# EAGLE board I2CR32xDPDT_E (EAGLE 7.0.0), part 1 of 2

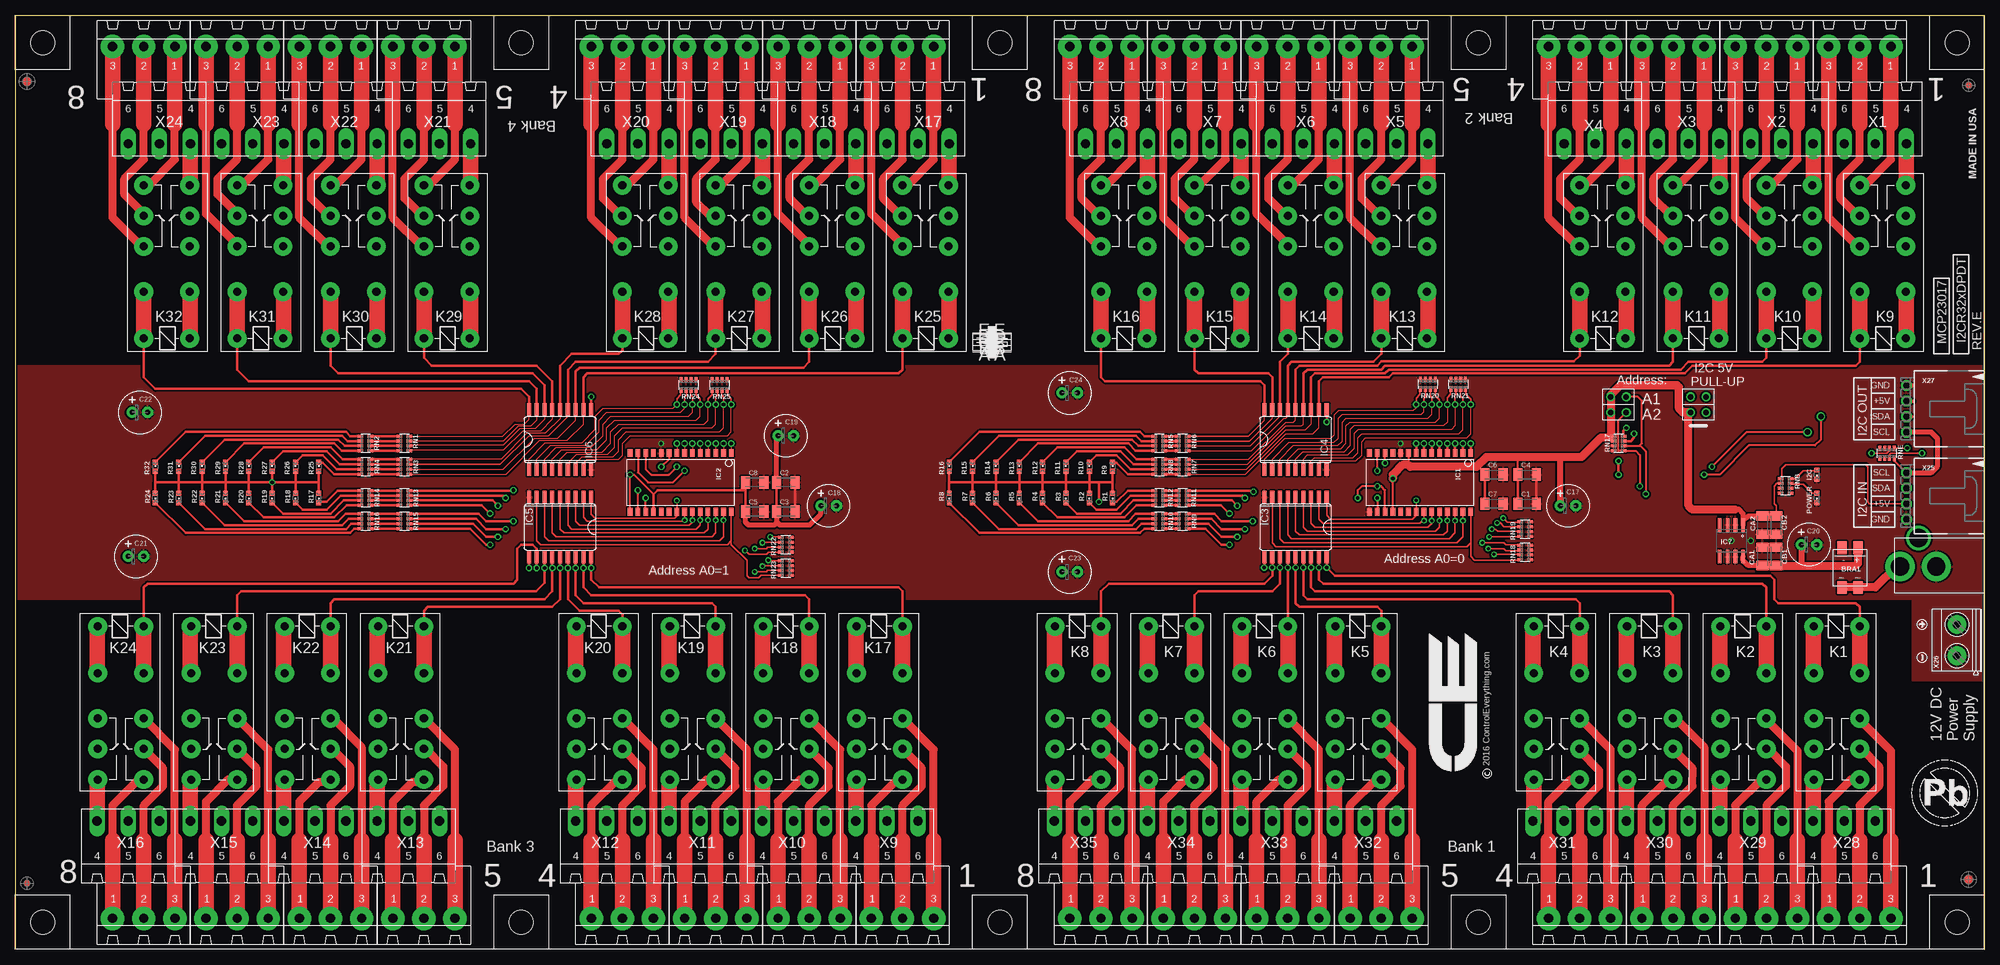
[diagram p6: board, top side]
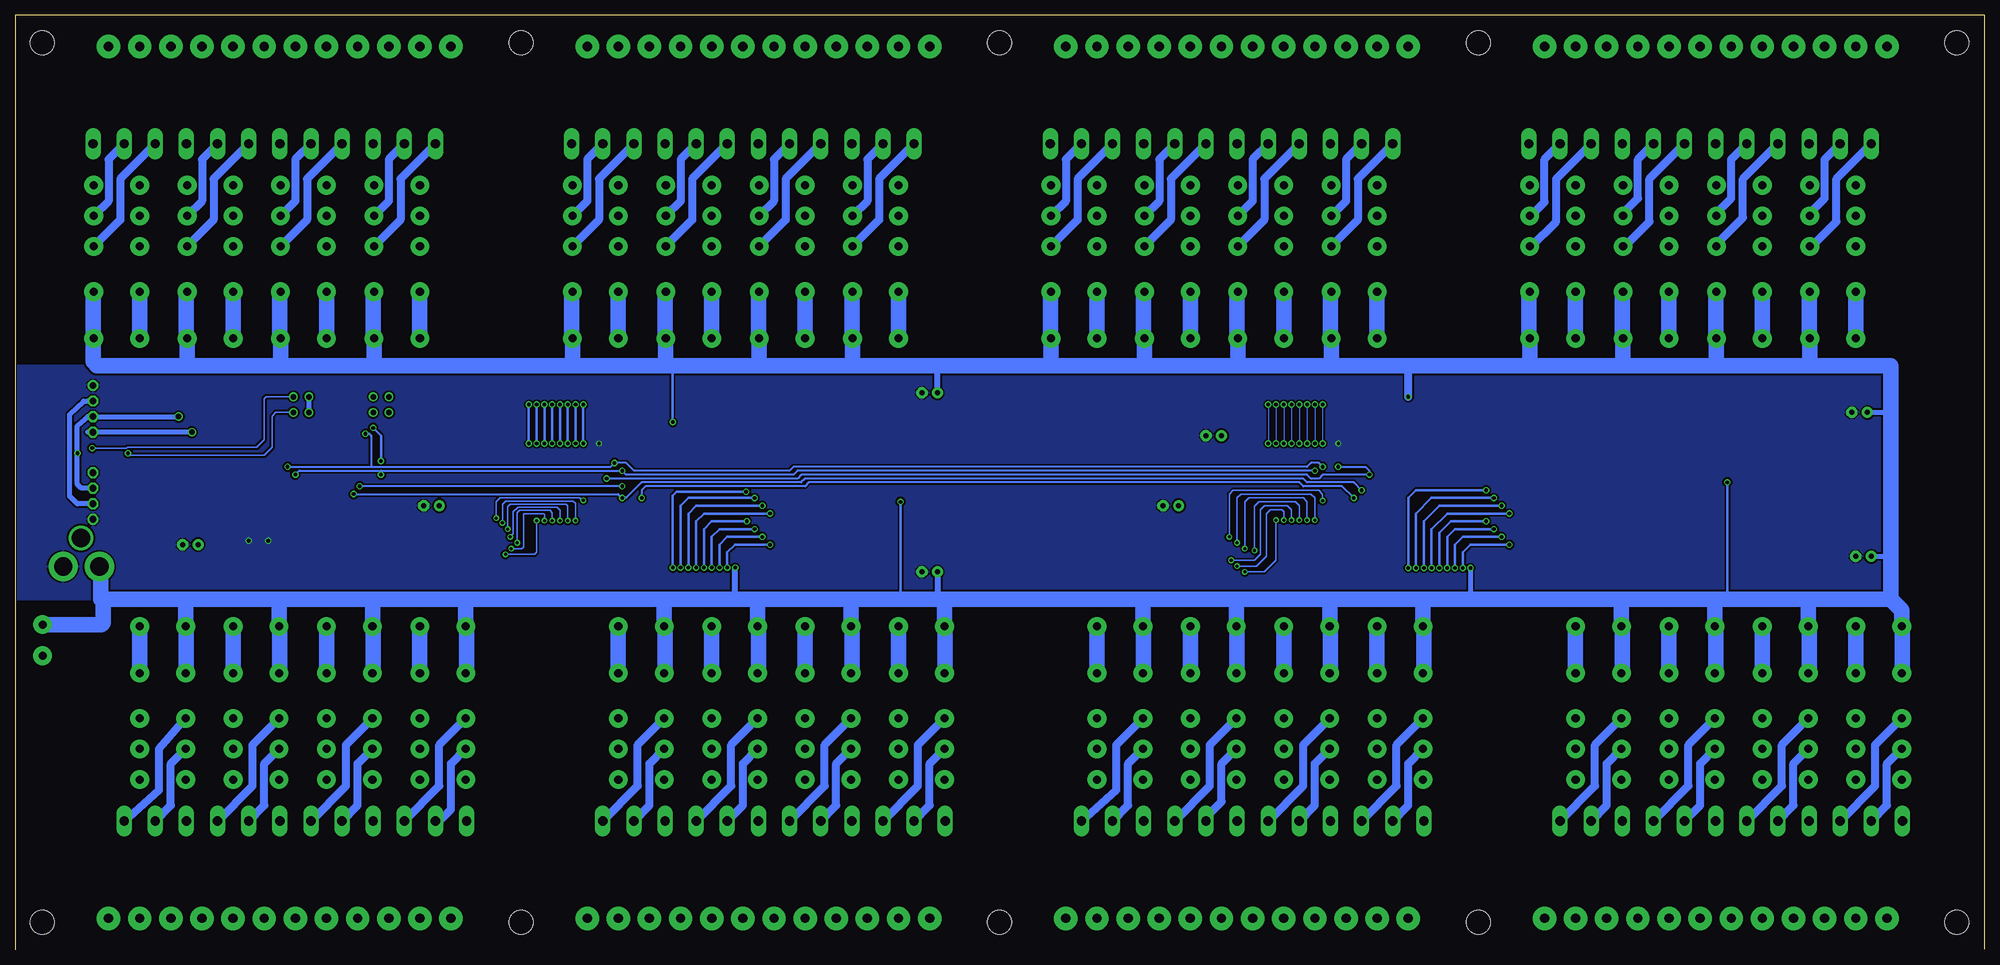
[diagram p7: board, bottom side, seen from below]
Size 321.29 x 152.41 mm. Coordinates in mm from the lower left corner, seen from the top.
Outline: 321.29,0 321.29,152.41 0,152.41 0,0.01
Copper layers (1*16): Top 0.035mm / dielectric 1.5mm / Bottom 0.035mm
Design rules "default": minimum track width 5mil, minimum drill 24mil, track to track 5mil, track to pad 5mil, pad to pad 5mil, via to via 5mil, smd to smd 5mil, copper to edge 10mil, drill to drill 8mil, minimum pad ring 10mil, minimum via ring 8mil, stop-mask expansion 2mil, vias tented up to drill 0mil, thermal gap 10mil

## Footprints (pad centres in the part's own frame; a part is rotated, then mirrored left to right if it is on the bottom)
MB2S = smd 1.55 x 2.1: + 0,-6.5; - 2.54,-6.5; ~@1 0,0; ~@2 2.54,0
_CA_.1UF_50V = smd 1.5 x 2: 1 -1.5,0; 2 1.5,0
_CB_10UF_25V = smd 1.5 x 2: 1 -1.5,0; 2 1.5,0
E-025X060 = drill 0.813 pad 1.778: + -1.27,0 | drill 0.813 pad 1.778 octagon: - 1.27,0
CC1206KRX7R9BB104 = smd 1.5 x 2: 1 -1.5,0; 2 1.5,0
TMK316F106ZL-T = smd 1.5 x 2: 1 -1.5,0; 2 1.5,0
CHIPLED_0603 = smd 0.8 x 0.8: A 0,-0.75; C 0,0.75
SO28W = smd 0.762 x 1.27: 1 -7.62,-4.78; 2 -6.35,-4.78; 3 -5.08,-4.78; 4 -3.81,-4.78; 5 -2.54,-4.78; 6 -1.27,-4.78; 7 0,-4.78; 8 1.27,-4.78; 9 2.54,-4.78; 10 3.81,-4.78; 11 5.08,-4.78; 12 6.35,-4.78; 13 7.62,-4.78; 14 8.89,-4.78; 15 8.89,4.78; 16 7.62,4.78; 17 6.35,4.78; 18 5.08,4.78; 19 3.81,4.78; 20 2.54,4.78; 21 1.27,4.78; 22 0,4.78; 23 -1.27,4.78; 24 -2.54,4.78; 25 -3.81,4.78; 26 -5.08,4.78; 27 -6.35,4.78; 28 -7.62,4.78
SO18L = smd 0.66 x 2.032: 1 -5.08,-4.902; 2 -3.81,-4.902; 3 -2.54,-4.902; 4 -1.27,-4.902; 5 0,-4.902; 6 1.27,-4.902; 7 2.54,-4.902; 8 3.81,-4.902; 9 5.08,-4.902; 10 5.08,4.902; 11 3.81,4.902; 12 2.54,4.902; 13 1.27,4.902; 14 0,4.902; 15 -1.27,4.902; 16 -2.54,4.902; 17 -3.81,4.902; 18 -5.08,4.902
_RGC_5V_SOIC8 = smd 0.6 x 2.2: 1 -1.905,-2.6; 2 -0.635,-2.6; 3 0.635,-2.6; 4 1.905,-2.6; 5 1.905,2.6; 6 0.635,2.6; 7 -0.635,2.6; 8 -1.905,2.6
G2R2 = drill 1.321 pad 3.048: 1 -2.54,-3.683; 2 -2.54,3.81; 3 5.08,-3.683; 4 5.08,3.81; O1 12.471,3.81; O2 12.471,-3.683; P1 17.45,3.81; P2 17.45,-3.683; S1 22.454,3.81; S2 22.454,-3.683
RNB = smd 0.5 x 0.9: 1 -1.2,-0.8; 2 -0.4,-0.8; 3 0.4,-0.8; 4 1.2,-0.8; 5 1.2,0.8; 6 0.4,0.8; 7 -0.4,0.8; 8 -1.2,0.8
RNE = smd 0.5 x 0.9: 1 -1.2,-0.8; 2 -0.4,-0.8; 3 0.4,-0.8; 4 1.2,-0.8; 5 1.2,0.8; 6 0.4,0.8; 7 -0.4,0.8; 8 -1.2,0.8
RND = smd 0.5 x 0.9: 1 -1.2,-0.8; 2 -0.4,-0.8; 3 0.4,-0.8; 4 1.2,-0.8; 5 1.2,0.8; 6 0.4,0.8; 7 -0.4,0.8; 8 -1.2,0.8
PCB_MOUNTING_HOLE = hole 3.962: 4.445,4.445
JUMPER_2X2 = drill 0.9: A1 0,2.54; A2 0,0; B1 2.54,2.54; B2 2.54,0
PJ-102A = drill 3 pad 4.8: RING 0.1,-3.39; TIP 0.1,-9.29 | drill 3 pad 3.251: RING_SW -4.6,-6.29
MDSTB3 = drill 1.524 pad 3.81: 1 -3.81,-10.795; 2 1.27,-10.795; 3 6.35,-10.795 | drill 1.524 pad 2.54 long: 4 -6.35,5.08; 5 -1.27,5.08; 6 3.81,5.08
15-91-04 = drill 1.1 pad 1.778 octagon: 1 -3.81,-7.62; 2 -1.27,-7.62; 3 1.27,-7.62; 4 3.81,-7.62
MKDSN1,5/2-5,08 = drill 1.3 pad 3.048: 1 -2.561,0.025; 2 2.519,0.025

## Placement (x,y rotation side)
BRA1  MB2S_  [MB2S]  300.67,59.07 180 top
C1  [_CA_.1UF_50V]  246.7,72.72 0 top
C2  _CB_10UF_25VC1206K  [_CB_10UF_25V]  125.73,76.21 0 top
C3  [_CA_.1UF_50V]  125.73,71.45 0 top
C4  _CB_10UF_25VC1206K  [_CB_10UF_25V]  246.7,77.48 0 top
C5  [_CA_.1UF_50V]  120.65,71.45 0 top
C6  _CB_10UF_25VC1206K  [_CB_10UF_25V]  241.3,77.48 0 top
C7  [_CA_.1UF_50V]  241.3,72.72 0 top
C8  _CB_10UF_25VC1206K  [_CB_10UF_25V]  120.65,76.21 0 top
C17  100uF  [E-025X060]  253.37,72.4 0 top
C18  100uF  [E-025X060]  132.72,72.4 0 top
C19  100uF  [E-025X060]  125.73,83.83 0 top
C20  100uF  [E-025X060]  292.74,66.05 0 top
C21  100uF  [E-025X060]  19.68,64.15 0 top
C22  100uF  [E-025X060]  20.32,87.64 0 top
C23  100uF  [E-025X060]  172.09,61.61 0 top
C24  100uF  [E-025X060]  172.09,90.82 0 top
CA1  [CC1206KRX7R9BB104]  285.12,64.15 270 top
CA2  [CC1206KRX7R9BB104]  285.12,69.23 90 top
CB1  [TMK316F106ZL-T]  287.34,64.15 270 top
CB2  [TMK316F106ZL-T]  287.34,69.23 90 top
I2C  LED_NCD  [CHIPLED_0603]  294,77.48 180 top
IC1  MCP23017SO  [SO28W]  229.87,76.21 180 top
IC2  MCP23017SO  [SO28W]  109.22,76.21 180 top
IC3  ULN2803  [SO18L]  208.91,68.91 180 top
IC4  ULN2803  [SO18L]  208.91,83.2 0 top
IC5  ULN2803  [SO18L]  88.9,68.91 180 top
IC6  ULN2803  [SO18L]  88.9,83.2 0 top
IC7  _RGC_5V_SOIC805  [_RGC_5V_SOIC8]  280.04,66.69 180 top
K1  G2R2  [G2R2]  297.18,50.18 270 top
K2  G2R2  [G2R2]  281.94,50.18 270 top
K3  G2R2  [G2R2]  266.7,50.18 270 top
K4  G2R2  [G2R2]  251.46,50.18 270 top
K5  G2R2  [G2R2]  219.07,50.18 270 top
K6  G2R2  [G2R2]  203.84,50.18 270 top
K7  G2R2  [G2R2]  188.59,50.18 270 top
K8  G2R2  [G2R2]  173.35,50.18 270 top
K9  G2R2  [G2R2]  304.8,102.25 90 top
K10  G2R2  [G2R2]  289.56,102.25 90 top
K11  G2R2  [G2R2]  274.32,102.25 90 top
K12  G2R2  [G2R2]  259.08,102.25 90 top
K13  G2R2  [G2R2]  226.69,102.25 90 top
K14  G2R2  [G2R2]  211.46,102.25 90 top
K15  G2R2  [G2R2]  196.22,102.25 90 top
K16  G2R2  [G2R2]  180.97,102.25 90 top
K17  G2R2  [G2R2]  140.97,50.18 270 top
K18  G2R2  [G2R2]  125.73,50.18 270 top
K19  G2R2  [G2R2]  110.49,50.18 270 top
K20  G2R2  [G2R2]  95.25,50.18 270 top
K21  G2R2  [G2R2]  62.87,50.18 270 top
K22  G2R2  [G2R2]  47.62,50.18 270 top
K23  G2R2  [G2R2]  32.38,50.18 270 top
K24  G2R2  [G2R2]  17.14,50.18 270 top
K25  G2R2  [G2R2]  148.59,102.25 90 top
K26  G2R2  [G2R2]  133.35,102.25 90 top
K27  G2R2  [G2R2]  118.11,102.25 90 top
K28  G2R2  [G2R2]  102.87,102.25 90 top
K29  G2R2  [G2R2]  70.48,102.25 90 top
K30  G2R2  [G2R2]  55.24,102.25 90 top
K31  G2R2  [G2R2]  40.01,102.25 90 top
K32  G2R2  [G2R2]  24.77,102.25 90 top
POWER  LED_NCD  [CHIPLED_0603]  294,73.67 180 top
R1  LED_NCD  [CHIPLED_0603]  179.07,73.67 180 top
R2  LED_NCD  [CHIPLED_0603]  175.26,73.67 180 top
R3  LED_NCD  [CHIPLED_0603]  171.45,73.67 180 top
R4  LED_NCD  [CHIPLED_0603]  167.64,73.67 180 top
R5  LED_NCD  [CHIPLED_0603]  163.83,73.67 180 top
R6  LED_NCD  [CHIPLED_0603]  160.02,73.67 180 top
R7  LED_NCD  [CHIPLED_0603]  156.21,73.67 180 top
R8  LED_NCD  [CHIPLED_0603]  152.4,73.67 180 top
R9  LED_NCD  [CHIPLED_0603]  179.07,78.75 0 top
R10  LED_NCD  [CHIPLED_0603]  175.26,78.75 0 top
R11  LED_NCD  [CHIPLED_0603]  171.45,78.75 0 top
R12  LED_NCD  [CHIPLED_0603]  167.64,78.75 0 top
R13  LED_NCD  [CHIPLED_0603]  163.83,78.75 0 top
R14  LED_NCD  [CHIPLED_0603]  160.02,78.75 0 top
R15  LED_NCD  [CHIPLED_0603]  156.21,78.75 0 top
R16  LED_NCD  [CHIPLED_0603]  152.4,78.75 0 top
R17  LED_NCD  [CHIPLED_0603]  49.53,73.67 180 top
R18  LED_NCD  [CHIPLED_0603]  45.72,73.67 180 top
R19  LED_NCD  [CHIPLED_0603]  41.91,73.67 180 top
R20  LED_NCD  [CHIPLED_0603]  38.1,73.67 180 top
R21  LED_NCD  [CHIPLED_0603]  34.29,73.67 180 top
R22  LED_NCD  [CHIPLED_0603]  30.48,73.67 180 top
R23  LED_NCD  [CHIPLED_0603]  26.67,73.67 180 top
R24  LED_NCD  [CHIPLED_0603]  22.86,73.67 180 top
R25  LED_NCD  [CHIPLED_0603]  49.53,78.75 0 top
R26  LED_NCD  [CHIPLED_0603]  45.72,78.75 0 top
R27  LED_NCD  [CHIPLED_0603]  41.91,78.75 0 top
R28  LED_NCD  [CHIPLED_0603]  38.1,78.75 0 top
R29  LED_NCD  [CHIPLED_0603]  34.29,78.75 0 top
R30  LED_NCD  [CHIPLED_0603]  30.48,78.75 0 top
R31  LED_NCD  [CHIPLED_0603]  26.67,78.75 0 top
R32  LED_NCD  [CHIPLED_0603]  22.86,78.75 0 top
RN1  _RNB_510  [RNB]  63.5,82.56 90 top
RN2  _RNB_510  [RNB]  57.15,82.56 90 top
RN3  _RNB_510  [RNB]  63.5,78.75 270 top
RN4  _RNB_510  [RNB]  57.15,78.75 270 top
RN5  _RNB_510  [RNB]  186.69,82.56 270 top
RN6  _RNB_510  [RNB]  190.5,82.56 270 top
RN7  _RNB_510  [RNB]  190.5,78.75 270 top
RN8  _RNB_510  [RNB]  186.69,78.75 270 top
RN9  _RNB_510  [RNB]  190.5,69.86 270 top
RN10  _RNB_510  [RNB]  186.69,69.86 270 top
RN11  _RNB_510  [RNB]  190.5,73.67 90 top
RN12  _RNB_510  [RNB]  186.69,73.67 90 top
RN13  _RNB_510  [RNB]  63.5,73.67 270 top
RN14  _RNB_510  [RNB]  57.15,73.67 270 top
RN15  _RNB_510  [RNB]  63.5,69.86 270 top
RN16  _RNB_510  [RNB]  57.15,69.86 270 top
RN17  _RNE_10K  [RNE]  261.62,82.56 270 top
RN18  _RNE_10K  [RNE]  246.38,64.78 90 top
RN19  _RNE_10K  [RNE]  246.38,68.59 90 top
RN20  _RNE_10K  [RNE]  230.5,92.21 180 top
RN21  _RNE_10K  [RNE]  235.46,92.21 180 top
RN22  _RNE_10K  [RNE]  125.73,66.05 90 top
RN23  _RNE_10K  [RNE]  125.73,62.24 90 top
RN24  _RNE_10K  [RNE]  109.86,92.09 180 top
RN25  _RNE_10K  [RNE]  114.94,92.09 180 top
RNB  _RNB_510  [RNB]  288.86,75.64 90 top
RNE  _RND_4.7K  [RND]  305.44,80.98 0 top
U$1  PCB_MOUNTING_HOLE  [PCB_MOUNTING_HOLE]  243.21,143.52 90 top
U$3  NOPB_LOGO_SYM  [NOPB_LOGO_SYM]  309.25,19.7 0 top
U$4  PCB_MOUNTING_HOLE  [PCB_MOUNTING_HOLE]  78.11,8.9 270 top
U$5  PCB_MOUNTING_HOLE  [PCB_MOUNTING_HOLE]  321.31,143.52 90 top
U$6  PCB_MOUNTING_HOLE  [PCB_MOUNTING_HOLE]  0,8.9 270 top
U$7  PCB_MOUNTING_HOLE  [PCB_MOUNTING_HOLE]  87,143.52 90 top
U$8  PCB_MOUNTING_HOLE  [PCB_MOUNTING_HOLE]  8.89,143.52 90 top
U$9  PCB_MOUNTING_HOLE  [PCB_MOUNTING_HOLE]  165.1,143.52 90 top
U$10  PCB_MOUNTING_HOLE  [PCB_MOUNTING_HOLE]  234.31,8.9 270 top
U$11  PCB_MOUNTING_HOLE  [PCB_MOUNTING_HOLE]  312.42,8.9 270 top
U$12  PCB_MOUNTING_HOLE  [PCB_MOUNTING_HOLE]  156.21,8.9 270 top
U$13  JUMPER_2X2  [JUMPER_2X2]  260.35,90.18 270 top
U$14  2.1MMJACK  [PJ-102A]  316.87,62.56 270 top
U$15  [VISION_REF15]  318.77,11.44 90 top
U$16  JUMPER_2X2  [JUMPER_2X2]  273.37,90.18 270 top
U$18  [VISION_REF10]  318.77,140.98 90 top
U$21  [ICON_USA]  320.04,125.74 90 top
U$22  [ICON_MINUS]  311.15,47.64 90 top
U$23  [VISION_REF15]  1.91,141.62 90 top
U$24  [ICON_PLUS]  311.15,53.04 0 top
U$28  [VISION_REF10]  1.91,10.81 90 top
X1  MDSTB3  [MDSTB3]  302.26,136.54 180 top
X2  MDSTB3  [MDSTB3]  287.02,136.54 180 top
X3  MDSTB3  [MDSTB3]  271.78,136.54 180 top
X4  MDSTB3  [MDSTB3]  256.54,136.54 180 top
X5  MDSTB3  [MDSTB3]  224.16,136.54 180 top
X6  MDSTB3  [MDSTB3]  208.91,136.54 180 top
X7  MDSTB3  [MDSTB3]  193.68,136.54 180 top
X8  MDSTB3  [MDSTB3]  178.44,136.54 180 top
X9  MDSTB3  [MDSTB3]  143.51,15.89 0 top
X10  MDSTB3  [MDSTB3]  128.27,15.89 0 top
X11  MDSTB3  [MDSTB3]  113.03,15.89 0 top
X12  MDSTB3  [MDSTB3]  97.79,15.89 0 top
X13  MDSTB3  [MDSTB3]  65.41,15.89 0 top
X14  MDSTB3  [MDSTB3]  50.16,15.89 0 top
X15  MDSTB3  [MDSTB3]  34.92,15.89 0 top
X16  MDSTB3  [MDSTB3]  19.68,15.89 0 top
X17  MDSTB3  [MDSTB3]  146.05,136.54 180 top
X18  MDSTB3  [MDSTB3]  130.81,136.54 180 top
X19  MDSTB3  [MDSTB3]  115.57,136.54 180 top
X20  MDSTB3  [MDSTB3]  100.33,136.54 180 top
X21  MDSTB3  [MDSTB3]  67.94,136.54 180 top
X22  MDSTB3  [MDSTB3]  52.7,136.54 180 top
X23  MDSTB3  [MDSTB3]  37.47,136.54 180 top
X24  MDSTB3  [MDSTB3]  22.23,136.54 180 top
X25  C-GRID-04-15-91-3044  [15-91-04]  316.23,73.99 270 top
X26  MKDSN1,5/2-5,08  [MKDSN1,5/2-5,08]  316.87,50.5 90 top
X27  C-GRID-04-15-91-3044  [15-91-04]  316.23,88.21 270 top
X28  MDSTB3  [MDSTB3]  299.72,15.89 0 top
X29  MDSTB3  [MDSTB3]  284.48,15.89 0 top
X30  MDSTB3  [MDSTB3]  269.24,15.89 0 top
X31  MDSTB3  [MDSTB3]  254,15.89 0 top
X32  MDSTB3  [MDSTB3]  221.62,15.89 0 top
X33  MDSTB3  [MDSTB3]  206.38,15.89 0 top
X34  MDSTB3  [MDSTB3]  191.13,15.89 0 top
X35  MDSTB3  [MDSTB3]  175.9,15.89 0 top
